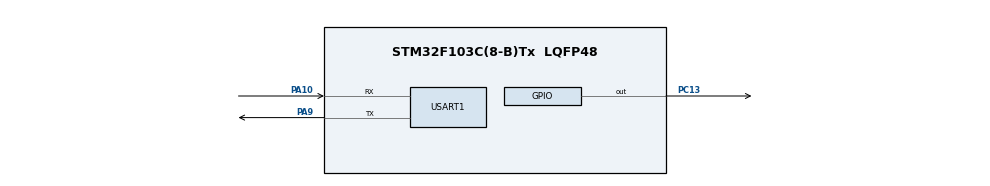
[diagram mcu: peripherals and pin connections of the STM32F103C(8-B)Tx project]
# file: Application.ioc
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Mcu.Family=STM32F1
Mcu.Name=STM32F103C(8-B)Tx
Mcu.Package=LQFP48
NVIC.PriorityGroup=NVIC_PRIORITYGROUP_4
PA10.Mode=Asynchronous
PA10.Signal=USART1_RX
PA13.Mode=Serial_Wire
PA13.Signal=SYS_JTMS-SWDIO
PA14.Mode=Serial_Wire
PA14.Signal=SYS_JTCK-SWCLK
PA9.Mode=Asynchronous
PA9.Signal=USART1_TX
PC13-TAMPER-RTC.Signal=GPIO_Output
PD0-OSC_IN.Mode=HSE-External-Oscillator
PD0-OSC_IN.Signal=RCC_OSC_IN
PD1-OSC_OUT.Mode=HSE-External-Oscillator
PD1-OSC_OUT.Signal=RCC_OSC_OUT
ProjectManager.HeapSize=0x200
ProjectManager.StackSize=0x400
ProjectManager.TargetToolchain=STM32CubeIDE
RCC.AHBFreq_Value=16000000
RCC.APB1Freq_Value=16000000
RCC.APB1TimFreq_Value=16000000
RCC.APB2Freq_Value=16000000
RCC.APB2TimFreq_Value=16000000
RCC.HCLKFreq_Value=16000000
RCC.PLLSourceVirtual=RCC_PLLSOURCE_HSE
RCC.SYSCLKFreq_VALUE=16000000
RCC.SYSCLKSource=RCC_SYSCLKSOURCE_PLLCLK
RCC.USBFreq_Value=16000000
USART1.VirtualMode=VM_ASYNC
board=custom

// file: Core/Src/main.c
/* USER CODE BEGIN Header */
/**
  ******************************************************************************
  * @file           : main.c
  * @brief          : Main program body
  ******************************************************************************
  * @attention
  *
  * Copyright (c) 2022 STMicroelectronics.
  * All rights reserved.
  *
  * This software is licensed under terms that can be found in the LICENSE file
  * in the root directory of this software component.
  * If no LICENSE file comes with this software, it is provided AS-IS.
  *
  ******************************************************************************
  */
/* USER CODE END Header */
#include "main.h"

/* USER CODE BEGIN Includes */
#include <stdio.h>
#include <string.h>
/* USER CODE END Includes */

/* USER CODE BEGIN PM */
#define MAJOR 0
#define MINOR 1
/* USER CODE END PM */

UART_HandleTypeDef huart1;

/* USER CODE BEGIN PV */
uint8_t APP_Version[2] = {MAJOR, MINOR};
/* USER CODE END PV */

void SystemClock_Config(void);
static void MX_GPIO_Init(void);
static void MX_USART1_UART_Init(void);

int main(void)
{

  /* MCU Configuration--------------------------------------------------------*/

  /* Reset of all peripherals, Initializes the Flash interface and the Systick. */
  HAL_Init();

  /* Configure the system clock */
  SystemClock_Config();

  /* Initialize all configured peripherals */
  MX_GPIO_Init();
  MX_USART1_UART_Init();
  /* USER CODE BEGIN 2 */
  printf("Application %d:%d Started!!!\n", APP_Version[0], APP_Version[1]);
  /* USER CODE END 2 */

  /* Infinite loop */
  while (1)
  {

    /* USER CODE BEGIN 3 */
	  HAL_GPIO_TogglePin(GPIOC, GPIO_PIN_13);
	  HAL_Delay(500);							//1sec delay
  }
  /* USER CODE END 3 */
}

void SystemClock_Config(void)
{
  RCC_OscInitTypeDef RCC_OscInitStruct = {0};
  RCC_ClkInitTypeDef RCC_ClkInitStruct = {0};

  /** Initializes the RCC Oscillators according to the specified parameters
  * in the RCC_OscInitTypeDef structure.
  */
  RCC_OscInitStruct.OscillatorType = RCC_OSCILLATORTYPE_HSI;
  RCC_OscInitStruct.HSIState = RCC_HSI_ON;
  RCC_OscInitStruct.HSICalibrationValue = RCC_HSICALIBRATION_DEFAULT;
  RCC_OscInitStruct.PLL.PLLState = RCC_PLL_NONE;
  if (HAL_RCC_OscConfig(&RCC_OscInitStruct) != HAL_OK)
  {
    Error_Handler();
  }

  /** Initializes the CPU, AHB and APB buses clocks
  */
  RCC_ClkInitStruct.ClockType = RCC_CLOCKTYPE_HCLK|RCC_CLOCKTYPE_SYSCLK
                              |RCC_CLOCKTYPE_PCLK1|RCC_CLOCKTYPE_PCLK2;
  RCC_ClkInitStruct.SYSCLKSource = RCC_SYSCLKSOURCE_HSI;
  RCC_ClkInitStruct.AHBCLKDivider = RCC_SYSCLK_DIV1;
  RCC_ClkInitStruct.APB1CLKDivider = RCC_HCLK_DIV1;
  RCC_ClkInitStruct.APB2CLKDivider = RCC_HCLK_DIV1;

  if (HAL_RCC_ClockConfig(&RCC_ClkInitStruct, FLASH_LATENCY_0) != HAL_OK)
  {
    Error_Handler();
  }
}

static void MX_USART1_UART_Init(void)
{

  huart1.Instance = USART1;
  huart1.Init.BaudRate = 115200;
  huart1.Init.WordLength = UART_WORDLENGTH_8B;
  huart1.Init.StopBits = UART_STOPBITS_1;
  huart1.Init.Parity = UART_PARITY_NONE;
  huart1.Init.Mode = UART_MODE_TX_RX;
  huart1.Init.HwFlowCtl = UART_HWCONTROL_NONE;
  huart1.Init.OverSampling = UART_OVERSAMPLING_16;
  if (HAL_UART_Init(&huart1) != HAL_OK)
  {
    Error_Handler();
  }

}

static void MX_GPIO_Init(void)
{
  GPIO_InitTypeDef GPIO_InitStruct = {0};

  /* GPIO Ports Clock Enable */
  __HAL_RCC_GPIOC_CLK_ENABLE();
  __HAL_RCC_GPIOA_CLK_ENABLE();

  /*Configure GPIO pin Output Level */
  HAL_GPIO_WritePin(GPIOC, GPIO_PIN_13, GPIO_PIN_RESET);

  /*Configure GPIO pin : PC13 */
  GPIO_InitStruct.Pin = GPIO_PIN_13;
  GPIO_InitStruct.Mode = GPIO_MODE_OUTPUT_PP;
  GPIO_InitStruct.Pull = GPIO_NOPULL;
  GPIO_InitStruct.Speed = GPIO_SPEED_FREQ_LOW;
  HAL_GPIO_Init(GPIOC, &GPIO_InitStruct);

}

/* USER CODE BEGIN 4 */
#ifdef __GNUC__
  /* With GCC, small printf (option LD Linker->Libraries->Small printf
     set to 'Yes') calls __io_putchar() */
int __io_putchar(int ch)
#else
int fputc(int ch, FILE *f)
#endif /* __GNUC__ */
{
  /* Place your implementation of fputc here */
  /* e.g. write a character to the UART3 and Loop until the end of transmission */
  HAL_UART_Transmit(&huart1, (uint8_t *)&ch, 1, HAL_MAX_DELAY);

  return ch;
}
/* USER CODE END 4 */

void Error_Handler(void)
{
  __disable_irq();
  while (1)
  {
  }
}
